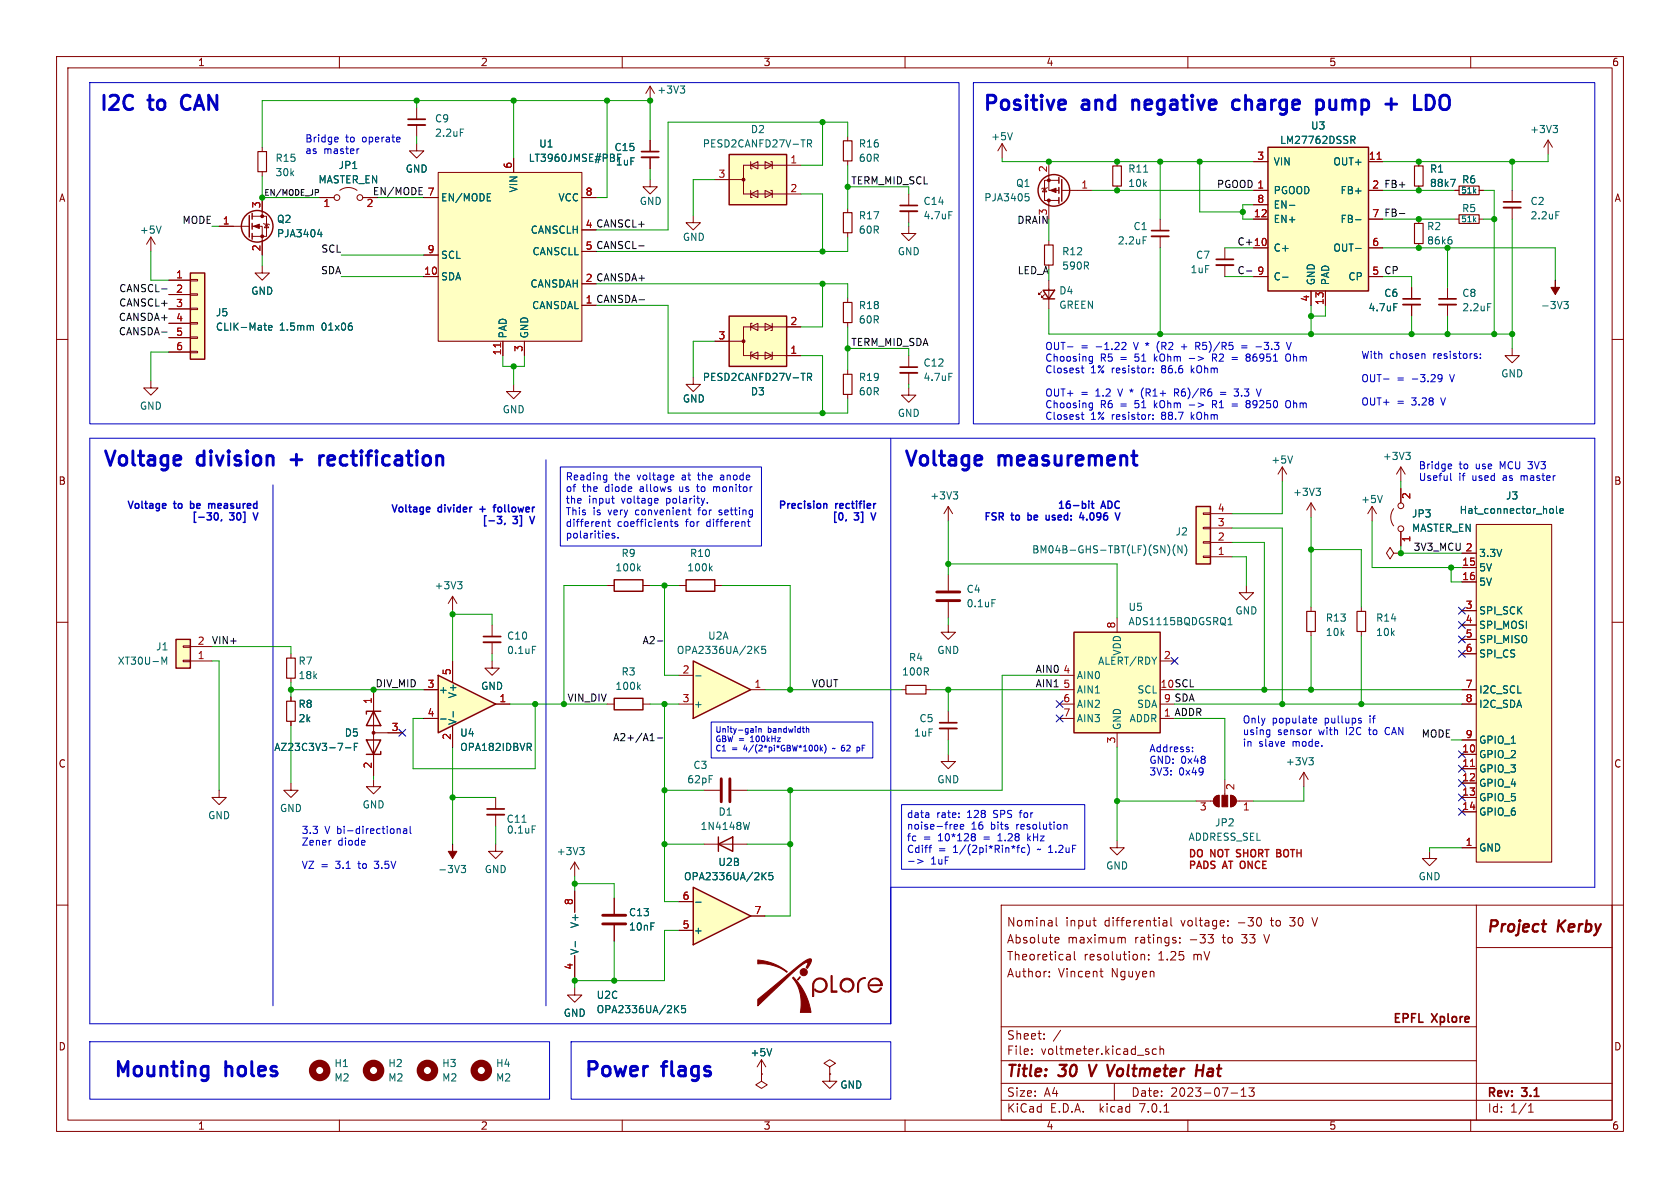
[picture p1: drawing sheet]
<svg xmlns="http://www.w3.org/2000/svg" width="297mm" height="210mm" viewBox="0 0 297 210" stroke-linecap="round" stroke-linejoin="round" font-family="sans-serif">
<defs><g id="words">
<g font-size="3.5" fill="#0000c2">
<text x="17.8" y="19.7">I2C</text>
<text x="26.6" y="19.7">to</text>
<text x="33.1" y="19.7">CAN</text>
<text x="174" y="19.7">Positive</text>
<text x="191.6" y="19.7">and</text>
<text x="201.2" y="19.7">negative</text>
<text x="219.7" y="19.7">charge</text>
<text x="235.2" y="19.7">pump</text>
<text x="248.2" y="19.7">+</text>
<text x="254" y="19.7">LDO</text>
<text x="18.4" y="82.6">Voltage</text>
<text x="35.1" y="82.6">division</text>
<text x="52.4" y="82.6">+</text>
<text x="58.2" y="82.6">rectification</text>
<text x="160" y="82.6">Voltage</text>
<text x="176.7" y="82.6">measurement</text>
<text x="20.3" y="190.5">Mounting</text>
<text x="40.1" y="190.5">holes</text>
<text x="103.5" y="190.5">Power</text>
<text x="117.5" y="190.5">flags</text>
</g>
<g font-size="2.8" fill="#840000">
<text x="262.7" y="165.3">Project</text>
<text x="275.2" y="165.3">Kerby</text>
<text x="178" y="190.8">Title:</text>
<text x="187.4" y="190.8">30</text>
<text x="193.3" y="190.8">V Voltmeter</text>
<text x="213.3" y="190.8">Hat</text>
</g>
<g font-size="2.1" fill="#840000">
<text x="178" y="166.9">Absolute</text>
<text x="178" y="163.9">Nominal</text>
<text x="188.4" y="163.9">input</text>
<text x="188.7" y="166.9">maximum</text>
<text x="195.2" y="163.9">differential</text>
<text x="200.6" y="166.9">ratings:</text>
<text x="208.8" y="163.9">voltage:</text>
<text x="210.3" y="166.9">-33</text>
<text x="216.3" y="166.9">to</text>
<text x="218.9" y="163.9">-30</text>
<text x="219.7" y="166.9">33</text>
<text x="223.8" y="166.9">V</text>
<text x="224.8" y="163.9">to</text>
<text x="228.3" y="163.9">30</text>
<text x="232.4" y="163.9">V</text>
<text x="178" y="172.9">Author:</text>
<text x="178" y="169.9">Theoretical</text>
<text x="187.1" y="172.9">Vincent</text>
<text x="191.6" y="169.9">resolution:</text>
<text x="196.4" y="172.9">Nguyen</text>
<text x="204.7" y="169.9">1.25</text>
<text x="211" y="169.9">mV</text>
<text x="178" y="183.9">Sheet:</text>
<text x="186.2" y="183.9">/</text>
<text x="245.9" y="181.1">EPFL</text>
<text x="252.9" y="181.1">Xplore</text>
<text x="178" y="186.6">File:</text>
<text x="184" y="186.6">voltmeter.kicad_sch</text>
<text x="178" y="196.8">KiCad</text>
<text x="178" y="194">Size:</text>
<text x="184.6" y="194">A4</text>
<text x="185.7" y="196.8">E.D.A.</text>
<text x="194.4" y="196.8">kicad</text>
<text x="200" y="194">Date:</text>
<text x="201.5" y="196.8">7.0.1</text>
<text x="206.9" y="194">2023-07-13</text>
<text x="263" y="194.2">Rev:</text>
<text x="263" y="196.8">Id:</text>
<text x="267" y="196.8">1/1</text>
<text x="269.2" y="194.2">3.1</text>
</g>
<g font-size="1.8" fill="#840000">
<text x="35" y="11.8">1</text>
<text x="85" y="11.8">2</text>
<text x="135" y="11.8">3</text>
<text x="185" y="11.8">4</text>
<text x="235" y="11.8">5</text>
<text x="285" y="11.8">6</text>
<text x="10.4" y="35.8">A</text>
<text x="285.4" y="35.8">A</text>
<text x="10.3" y="85.8">B</text>
<text x="285.3" y="85.8">B</text>
<text x="10.3" y="135.8">C</text>
<text x="285.3" y="135.8">C</text>
<text x="10.3" y="185.8">D</text>
<text x="285.3" y="185.8">D</text>
<text x="35" y="199.8">1</text>
<text x="85" y="199.8">2</text>
<text x="135" y="199.8">3</text>
<text x="185" y="199.8">4</text>
<text x="235" y="199.8">5</text>
<text x="285" y="199.8">6</text>
</g>
<g font-size="1.8" fill="#006464">
<text x="116.1" y="16.7">+3V3</text>
<text x="76.8" y="21.8">C9</text>
<text x="132.7" y="23.7">D2</text>
<text x="231.7" y="23.1">U3</text>
<text x="270.4" y="23.7">+3V3</text>
<text x="48.6" y="28.8">R15</text>
<text x="76.8" y="24.3">2.2uF</text>
<text x="93.4" y="28.8">LT3960JMSE#PBF</text>
<text x="95.3" y="26.2">U1</text>
<text x="108.6" y="26.9">C15</text>
<text x="108.8" y="29.4">1uF</text>
<text x="124.2" y="26.2">PESD2CANFD27V-TR</text>
<text x="151.8" y="26.2">R16</text>
<text x="151.8" y="28.8">60R</text>
<text x="175.2" y="25">+5V</text>
<text x="225.2" y="29.4">VIN</text>
<text x="226.2" y="25.6">LM27762DSSR</text>
<text x="235.6" y="29.4">OUT+</text>
<text x="48.6" y="31.3">30k</text>
<text x="56.2" y="32.6">MASTER_EN</text>
<text x="59.8" y="30">JP1</text>
<text x="71.7" y="30.7">GND</text>
<text x="78" y="35.8">EN/MODE</text>
<text x="91.6" y="34.1" transform="rotate(-90 91.6 34.1)">VIN</text>
<text x="98.6" y="35.8">VCC</text>
<text x="173.9" y="35.8">PJA3405</text>
<text x="179.6" y="33.2">Q1</text>
<text x="199.4" y="30.7">R11</text>
<text x="199.4" y="33.2">10k</text>
<text x="225.2" y="34.5">PGOOD</text>
<text x="236.9" y="34.5">FB+</text>
<text x="252.7" y="30.7">R1</text>
<text x="252.7" y="33.2">88k7</text>
<text x="258.4" y="32.6">R6</text>
<text x="24.7" y="41.5">+5V</text>
<text x="48.9" y="39.6">Q2</text>
<text x="93.7" y="41.5">CANSCLH</text>
<text x="113" y="36.4">GND</text>
<text x="151.8" y="38.9">R17</text>
<text x="151.8" y="41.5">60R</text>
<text x="163.2" y="36.4">C14</text>
<text x="163.2" y="38.9">4.7uF</text>
<text x="200.3" y="40.8">C1</text>
<text x="225.2" y="39.6">EN+</text>
<text x="225.2" y="37">EN-</text>
<text x="236.9" y="39.6">FB-</text>
<text x="252.2" y="40.8">R2</text>
<text x="258.4" y="37.7">R5</text>
<text x="270.5" y="36.4">C2</text>
<text x="270.5" y="38.9">2.2uF</text>
<text x="48.9" y="42.1">PJA3404</text>
<text x="78" y="45.9">SCL</text>
<text x="94" y="45.3">CANSCLL</text>
<text x="120.7" y="42.7">GND</text>
<text x="158.7" y="45.3">GND</text>
<text x="187.7" y="45.3">R12</text>
<text x="187.7" y="47.8">590R</text>
<text x="197.5" y="43.4">2.2uF</text>
<text x="211.4" y="45.9">C7</text>
<text x="225.2" y="44.6">C+</text>
<text x="235.6" y="44.6">OUT-</text>
<text x="252.2" y="43.4">86k6</text>
<text x="44.4" y="52.3">GND</text>
<text x="78" y="49.7">SDA</text>
<text x="93.6" y="51">CANSDAH</text>
<text x="187.2" y="52.2">D4</text>
<text x="210.4" y="48.5">1uF</text>
<text x="225.2" y="49.7">C-</text>
<text x="232.6" y="50.4" transform="rotate(-90 232.6 50.4)">GND</text>
<text x="235.1" y="50.4" transform="rotate(-90 235.1 50.4)">PAD</text>
<text x="238.3" y="49.7">CP</text>
<text x="244.7" y="52.6">C6</text>
<text x="258.5" y="52.6">C8</text>
<text x="38.1" y="56.1">J5</text>
<text x="38.1" y="58.6">CLIK-Mate</text>
<text x="49.4" y="58.6">1.5mm</text>
<text x="56.9" y="58.6">01x06</text>
<text x="89.7" y="59.8" transform="rotate(-90 89.7 59.8)">PAD</text>
<text x="93.5" y="59.8" transform="rotate(-90 93.5 59.8)">GND</text>
<text x="93.9" y="54.8">CANSDAL</text>
<text x="151.8" y="54.8">R18</text>
<text x="151.8" y="57.3">60R</text>
<text x="187.2" y="54.7">GREEN</text>
<text x="241.9" y="55.2">4.7uF</text>
<text x="258.5" y="55.2">2.2uF</text>
<text x="272.4" y="54.8">-3V3</text>
<text x="163.2" y="65">C12</text>
<text x="120.7" y="71.3">GND</text>
<text x="124.2" y="67.5">PESD2CANFD27V-TR</text>
<text x="132.7" y="70">D3</text>
<text x="151.8" y="67.5">R19</text>
<text x="151.8" y="70">60R</text>
<text x="163.2" y="67.5">4.7uF</text>
<text x="265.3" y="66.9">GND</text>
<text x="24.7" y="72.6">GND</text>
<text x="88.8" y="73.2">GND</text>
<text x="158.7" y="73.9">GND</text>
<text x="224.7" y="82.1">+5V</text>
<text x="244.4" y="81.5">+3V3</text>
<text x="164.4" y="88.5">+3V3</text>
<text x="228.5" y="87.8">+3V3</text>
<text x="240.6" y="89.1">+5V</text>
<text x="266.2" y="88.5">J3</text>
<text x="207.8" y="94.8">J2</text>
<text x="249.6" y="91.6">JP3</text>
<text x="249.6" y="94.2">MASTER_EN</text>
<text x="258" y="91">Hat_connector_hole</text>
<text x="108.7" y="101.2">100k</text>
<text x="109.8" y="98.6">R9</text>
<text x="121.4" y="101.2">100k</text>
<text x="121.9" y="98.6">R10</text>
<text x="182.4" y="98">BM04B-GHS-TBT(LF)(SN)(N)</text>
<text x="261.5" y="101.2">5V</text>
<text x="261.5" y="98.6">3.3V</text>
<text x="76.8" y="104.3">+3V3</text>
<text x="170.8" y="105">C4</text>
<text x="170.8" y="107.5">0.1uF</text>
<text x="261.5" y="103.7">5V</text>
<text x="89.6" y="113.2">C10</text>
<text x="125.1" y="113.2">U2A</text>
<text x="199.4" y="110.7">ADS1115BQDGSRQ1</text>
<text x="199.4" y="108.1">U5</text>
<text x="218.3" y="108.8">GND</text>
<text x="234.3" y="110">R13</text>
<text x="234.3" y="112.6">10k</text>
<text x="243.2" y="110">R14</text>
<text x="243.2" y="112.6">10k</text>
<text x="261.5" y="108.8">SPI_SCK</text>
<text x="261.5" y="111.3">SPI_MOSI</text>
<text x="261.5" y="113.9">SPI_MISO</text>
<text x="20.8" y="117.7">XT30U-M</text>
<text x="27.5" y="115.1">J1</text>
<text x="52.7" y="117.7">R7</text>
<text x="89.6" y="115.8">0.1uF</text>
<text x="109.8" y="119.6">R3</text>
<text x="119.6" y="115.8">OPA2336UA/2K5</text>
<text x="159.4" y="119.6">100R</text>
<text x="160.6" y="117">R4</text>
<text x="165.6" y="115.8">GND</text>
<text x="194" y="117.7">ALERT/RDY</text>
<text x="198.3" y="116" transform="rotate(-90 198.3 116)">VDD</text>
<text x="261.5" y="116.4">SPI_CS</text>
<text x="52.7" y="125.3">R8</text>
<text x="52.7" y="120.2">18k</text>
<text x="77.6" y="122.7">+</text>
<text x="80.8" y="123.6" transform="rotate(-90 80.8 123.6)">V+</text>
<text x="85" y="122.1">GND</text>
<text x="108.7" y="122.1">100k</text>
<text x="122.7" y="125.3">+</text>
<text x="190.4" y="120.2">AIN0</text>
<text x="190.4" y="122.7">AIN1</text>
<text x="190.4" y="125.3">AIN2</text>
<text x="200.9" y="125.3">SDA</text>
<text x="201" y="122.7">SCL</text>
<text x="261.5" y="122.7">I2C_SCL</text>
<text x="261.5" y="125.3">I2C_SDA</text>
<text x="52.7" y="127.8">2k</text>
<text x="60.9" y="130.4">D5</text>
<text x="80.8" y="128.1" transform="rotate(-90 80.8 128.1)">V-</text>
<text x="81.3" y="130.4">U4</text>
<text x="161.5" y="130.4">1uF</text>
<text x="162.5" y="127.8">C5</text>
<text x="190.4" y="127.8">AIN3</text>
<text x="198.3" y="129" transform="rotate(-90 198.3 129)">GND</text>
<text x="199.6" y="127.8">ADDR</text>
<text x="261.5" y="131.6">GPIO_1</text>
<text x="48.4" y="132.9">AZ23C3V3-7-F</text>
<text x="81.3" y="132.9">OPA182IDBVR</text>
<text x="122.5" y="136.1">C3</text>
<text x="227.3" y="135.4">+3V3</text>
<text x="261.5" y="134.2">GPIO_2</text>
<text x="261.5" y="136.7">GPIO_3</text>
<text x="49.4" y="143.7">GND</text>
<text x="64" y="143.1">GND</text>
<text x="121.4" y="138.6">62pF</text>
<text x="165.6" y="138.6">GND</text>
<text x="261.5" y="139.3">GPIO_4</text>
<text x="261.5" y="141.8">GPIO_5</text>
<text x="36.7" y="145">GND</text>
<text x="89.5" y="145.6">C11</text>
<text x="89.5" y="147.5">0.1uF</text>
<text x="123.8" y="146.9">1N4148W</text>
<text x="127" y="144.3">D1</text>
<text x="210.1" y="148.8">ADDRESS_SEL</text>
<text x="214.7" y="146.2">JP2</text>
<text x="261.5" y="144.3">GPIO_6</text>
<text x="77.4" y="154.5">-3V3</text>
<text x="85.6" y="154.5">GND</text>
<text x="98.4" y="151.3">+3V3</text>
<text x="120.9" y="155.8">OPA2336UA/2K5</text>
<text x="126.9" y="153.2">U2B</text>
<text x="195.5" y="153.9">GND</text>
<text x="250.7" y="155.8">GND</text>
<text x="261.5" y="150.7">GND</text>
<text x="102.4" y="164.2" transform="rotate(-90 102.4 164.2)">V+</text>
<text x="111.1" y="162.1">C13</text>
<text x="111.1" y="164.7">10nF</text>
<text x="122.7" y="165.3">+</text>
<text x="102.4" y="168.8" transform="rotate(-90 102.4 168.8)">V-</text>
<text x="99.6" y="179.9">GND</text>
<text x="105.4" y="176.7">U2C</text>
<text x="105.4" y="179.3">OPA2336UA/2K5</text>
<text x="59.1" y="188.8">H1</text>
<text x="59.1" y="191.3">M2</text>
<text x="68.6" y="188.8">H2</text>
<text x="68.6" y="191.3">M2</text>
<text x="78.1" y="188.8">H3</text>
<text x="78.1" y="191.3">M2</text>
<text x="87.6" y="188.8">H4</text>
<text x="87.6" y="191.3">M2</text>
<text x="132.6" y="186.9">+5V</text>
<text x="148.5" y="192.6">GND</text>
</g>
<g font-size="1.8" fill="#0000c2">
<text x="54" y="25.2">Bridge</text>
<text x="54" y="27.3">as</text>
<text x="57.2" y="27.3">master</text>
<text x="61.1" y="25.2">to</text>
<text x="64.1" y="25.2">operate</text>
<text x="184.8" y="62">OUT-</text>
<text x="184.8" y="64">Choosing</text>
<text x="191.1" y="62">=</text>
<text x="193.7" y="62">-1.22</text>
<text x="194.5" y="64">R5</text>
<text x="198.1" y="64">=</text>
<text x="200.6" y="62">V *</text>
<text x="200.8" y="64">51</text>
<text x="204.3" y="64">kOhm</text>
<text x="204.9" y="62">(R2</text>
<text x="209.3" y="62">+</text>
<text x="212" y="62">R5)/R5</text>
<text x="214.8" y="64">R2</text>
<text x="221.1" y="64">86951</text>
<text x="222.9" y="62">-3.3</text>
<text x="228.2" y="64">Ohm</text>
<text x="240.7" y="63.5">With</text>
<text x="245.7" y="63.5">chosen</text>
<text x="253.4" y="63.5">resistors:</text>
<text x="184.8" y="66.1">Closest</text>
<text x="184.8" y="70.2">OUT+</text>
<text x="191.1" y="70.2">=</text>
<text x="192.8" y="66.1">1% resistor:</text>
<text x="193.7" y="70.2">1.2</text>
<text x="197.9" y="70.2">V *</text>
<text x="202.1" y="70.2">(R1+</text>
<text x="205.5" y="66.1">86.6</text>
<text x="208.1" y="70.2">R6)/R6</text>
<text x="210.8" y="66.1">kOhm</text>
<text x="219" y="70.2">3.3</text>
<text x="240.7" y="67.6">OUT-</text>
<text x="240.7" y="71.8">OUT+</text>
<text x="247" y="67.6">=</text>
<text x="247" y="71.8">=</text>
<text x="249.6" y="67.6">-3.29</text>
<text x="249.6" y="71.8">3.28</text>
<text x="255" y="71.8">V</text>
<text x="256.5" y="67.6">V</text>
<text x="184.8" y="72.2">Choosing</text>
<text x="184.8" y="74.3">Closest</text>
<text x="192.8" y="74.3">1% resistor:</text>
<text x="194.5" y="72.2">R6</text>
<text x="198.1" y="72.2">=</text>
<text x="200.8" y="72.2">51</text>
<text x="204.3" y="72.2">kOhm</text>
<text x="205.5" y="74.3">88.7</text>
<text x="210.8" y="74.3">kOhm</text>
<text x="214.8" y="72.2">R1</text>
<text x="221.1" y="72.2">89250</text>
<text x="228.2" y="72.2">Ohm</text>
<text x="250.8" y="83">Bridge</text>
<text x="258" y="83">to</text>
<text x="260.9" y="83">use</text>
<text x="265.3" y="83">MCU 3V3</text>
<text x="100" y="85.2">Reading</text>
<text x="100" y="87.2">of</text>
<text x="100" y="89.3">the</text>
<text x="103" y="87.2">the</text>
<text x="104.1" y="89.3">input</text>
<text x="107" y="87.2">diode</text>
<text x="108.7" y="85.2">the</text>
<text x="109.9" y="89.3">voltage</text>
<text x="112.7" y="85.2">voltage</text>
<text x="113.3" y="87.2">allows</text>
<text x="117.9" y="89.3">polarity.</text>
<text x="120.4" y="87.2">us</text>
<text x="120.7" y="85.2">at</text>
<text x="123.6" y="87.2">to</text>
<text x="123.7" y="85.2">the</text>
<text x="126.6" y="87.2">monitor</text>
<text x="127.7" y="85.2">anode</text>
<text x="250.8" y="85.1">Useful</text>
<text x="257.9" y="85.1">if</text>
<text x="260.3" y="85.1">used</text>
<text x="265.8" y="85.1">as</text>
<text x="269.1" y="85.1">master</text>
<text x="22.2" y="90">Voltage</text>
<text x="30.5" y="90">to</text>
<text x="33.6" y="92.1">[-30,</text>
<text x="33.8" y="90">be</text>
<text x="37.4" y="90">measured</text>
<text x="40.4" y="92.1">30]</text>
<text x="45" y="92.1">V</text>
<text x="68.8" y="90.7">Voltage</text>
<text x="77.2" y="90.7">divider</text>
<text x="84.9" y="90.7">+</text>
<text x="84.9" y="92.7">[-3,</text>
<text x="87.8" y="90.7">follower</text>
<text x="90.5" y="92.7">3]</text>
<text x="93.9" y="92.7">V</text>
<text x="100" y="91.3">This</text>
<text x="100" y="93.4">different</text>
<text x="100" y="95.4">polarities.</text>
<text x="104.9" y="91.3">is</text>
<text x="107.6" y="91.3">very</text>
<text x="109.2" y="93.4">coefficients</text>
<text x="112.5" y="91.3">convenient</text>
<text x="121.3" y="93.4">for</text>
<text x="123.7" y="91.3">for</text>
<text x="125.1" y="93.4">different</text>
<text x="127.5" y="91.3">setting</text>
<text x="137.3" y="90">Precision</text>
<text x="146.8" y="92.1">[0,</text>
<text x="147.4" y="90">rectifier</text>
<text x="150.8" y="92.1">3]</text>
<text x="154.2" y="92.1">V</text>
<text x="173.7" y="92.1">FSR</text>
<text x="178.6" y="92.1">to</text>
<text x="181.8" y="92.1">be</text>
<text x="185.4" y="92.1">used:</text>
<text x="186.7" y="90">16-bit</text>
<text x="191.8" y="92.1">4.096</text>
<text x="194.5" y="90">ADC</text>
<text x="219.7" y="128">Only</text>
<text x="219.7" y="130">using</text>
<text x="224.9" y="128">populate</text>
<text x="225.9" y="130">sensor</text>
<text x="233.2" y="130">with</text>
<text x="234.2" y="128">pullups</text>
<text x="238.1" y="130">I2C</text>
<text x="242.3" y="128">if</text>
<text x="242.3" y="130">to</text>
<text x="245.3" y="130">CAN</text>
<text x="203.2" y="133">Address:</text>
<text x="203.2" y="135.1">GND: 0x48</text>
<text x="203.2" y="137.2">3V3:</text>
<text x="208.4" y="137.2">0x49</text>
<text x="219.7" y="132.1">in</text>
<text x="222.6" y="132.1">slave</text>
<text x="228.6" y="132.1">mode.</text>
<text x="53.3" y="147.5">3.3</text>
<text x="53.3" y="149.6">Zener</text>
<text x="57.5" y="147.5">V bi-directional</text>
<text x="59.8" y="149.6">diode</text>
<text x="160.3" y="144.8">data</text>
<text x="160.3" y="146.9">noise-free</text>
<text x="160.3" y="149">fc</text>
<text x="163.2" y="149">=</text>
<text x="165.6" y="144.8">rate:</text>
<text x="165.9" y="149">10*128</text>
<text x="171.1" y="144.8">128</text>
<text x="171.7" y="146.9">16</text>
<text x="174" y="149">=</text>
<text x="175.2" y="146.9">bits</text>
<text x="175.8" y="144.8">SPS</text>
<text x="176.7" y="149">1.28</text>
<text x="179.8" y="146.9">resolution</text>
<text x="180.6" y="144.8">for</text>
<text x="182" y="149">kHz</text>
<text x="53.3" y="153.7">VZ =</text>
<text x="59.4" y="153.7">3.1</text>
<text x="63.5" y="153.7">to</text>
<text x="66.5" y="153.7">3.5V</text>
<text x="160.3" y="151">Cdiff</text>
<text x="164.6" y="153.1">1uF</text>
<text x="165.9" y="151">=</text>
<text x="168.6" y="151">1/(2pi*Rin*fc)</text>
<text x="183.6" y="151">~ 1.2uF</text>
</g>
<g font-size="1.8" fill="#a90000">
<text x="90.6" y="29.9" transform="rotate(-90 90.6 29.9)">6</text>
<text x="139.7" y="29">1</text>
<text x="222.2" y="28.3">3</text>
<text x="241.9" y="28.3">11</text>
<text x="75.5" y="34.7">7</text>
<text x="103.5" y="34.7">8</text>
<text x="127" y="31.5">3</text>
<text x="139.7" y="34">2</text>
<text x="185.2" y="30.5" transform="rotate(-90 185.2 30.5)">2</text>
<text x="191.1" y="33.4">1</text>
<text x="222.2" y="35.9">8</text>
<text x="222.2" y="33.4">1</text>
<text x="242.5" y="33.4">2</text>
<text x="39.3" y="39.8">1</text>
<text x="46.1" y="36.9" transform="rotate(-90 46.1 36.9)">3</text>
<text x="57.1" y="36.8">1</text>
<text x="64.7" y="36.8">2</text>
<text x="103.5" y="40.4">4</text>
<text x="185.2" y="38.1" transform="rotate(-90 185.2 38.1)">3</text>
<text x="221.6" y="38.5">12</text>
<text x="242.5" y="38.5">7</text>
<text x="46.1" y="44.5" transform="rotate(-90 46.1 44.5)">2</text>
<text x="75.5" y="44.8">9</text>
<text x="103.5" y="44.2">5</text>
<text x="221.6" y="43.6">10</text>
<text x="242.5" y="43.6">6</text>
<text x="31.1" y="49.3">1</text>
<text x="31.1" y="51.8">2</text>
<text x="74.9" y="48.6">10</text>
<text x="103.5" y="53.7">1</text>
<text x="103.5" y="49.9">2</text>
<text x="222.2" y="48.6">9</text>
<text x="231.5" y="53.4" transform="rotate(-90 231.5 53.4)">4</text>
<text x="234.1" y="54" transform="rotate(-90 234.1 54)">13</text>
<text x="242.5" y="48.6">5</text>
<text x="31.1" y="54.4">3</text>
<text x="31.1" y="56.9">4</text>
<text x="31.1" y="59.4">5</text>
<text x="139.7" y="57.5">2</text>
<text x="31.1" y="62">6</text>
<text x="88.6" y="62.9" transform="rotate(-90 88.6 62.9)">11</text>
<text x="92.5" y="62.3" transform="rotate(-90 92.5 62.3)">3</text>
<text x="127" y="60.1">3</text>
<text x="139.7" y="62.6">1</text>
<text x="249.6" y="88.3" transform="rotate(-90 249.6 88.3)">2</text>
<text x="215.2" y="95.6">2</text>
<text x="215.2" y="93.1">3</text>
<text x="215.2" y="90.6">4</text>
<text x="249.6" y="95.9" transform="rotate(-90 249.6 95.9)">1</text>
<text x="215.2" y="98.2">1</text>
<text x="258.4" y="100.1">15</text>
<text x="259" y="97.5">2</text>
<text x="258.4" y="102.6">16</text>
<text x="259" y="107.7">3</text>
<text x="197.2" y="111.2" transform="rotate(-90 197.2 111.2)">8</text>
<text x="259" y="110.2">4</text>
<text x="259" y="112.8">5</text>
<text x="34.9" y="116.6">1</text>
<text x="34.9" y="114">2</text>
<text x="79.8" y="119.4" transform="rotate(-90 79.8 119.4)">5</text>
<text x="120.6" y="119.1">2</text>
<text x="187.9" y="119.1">4</text>
<text x="205.7" y="116.6">2</text>
<text x="259" y="115.3">6</text>
<text x="65.8" y="124.5" transform="rotate(-90 65.8 124.5)">1</text>
<text x="75.5" y="121.7">3</text>
<text x="88.2" y="124.2">1</text>
<text x="120.6" y="124.2">3</text>
<text x="133.3" y="121.7">1</text>
<text x="187.9" y="121.7">5</text>
<text x="187.9" y="124.2">6</text>
<text x="259" y="121.7">7</text>
<text x="259" y="124.2">8</text>
<text x="69.2" y="129.3">3</text>
<text x="75.5" y="126.7">4</text>
<text x="79.8" y="130.8" transform="rotate(-90 79.8 130.8)">2</text>
<text x="187.9" y="126.7">7</text>
<text x="197.2" y="131.5" transform="rotate(-90 197.2 131.5)">3</text>
<text x="259" y="130.6">9</text>
<text x="65.8" y="135.9" transform="rotate(-90 65.8 135.9)">2</text>
<text x="258.4" y="133.1">10</text>
<text x="258.4" y="135.6">11</text>
<text x="212.1" y="143.5">3</text>
<text x="218.4" y="139.7" transform="rotate(-90 218.4 139.7)">2</text>
<text x="219.7" y="143.5">1</text>
<text x="258.4" y="138.2">12</text>
<text x="258.4" y="140.7">13</text>
<text x="258.4" y="143.3">14</text>
<text x="259" y="149.6">1</text>
<text x="101.3" y="160.1" transform="rotate(-90 101.3 160.1)">8</text>
<text x="120.6" y="159.1">6</text>
<text x="133.3" y="161.7">7</text>
<text x="120.6" y="164.2">5</text>
<text x="101.3" y="171.5" transform="rotate(-90 101.3 171.5)">4</text>
</g>
<g font-size="1.8" fill="#0f0f0f">
<text x="65.8" y="34.6">EN/MODE</text>
<text x="150.5" y="32.7">TERM_MID_SCL</text>
<text x="215" y="33.3">PGOOD 1</text>
<text x="242.5" y="33.4">2 FB+</text>
<text x="32.1" y="39.7">MODE</text>
<text x="103.5" y="40.4">4 CANSCL+</text>
<text x="179.7" y="39.7">DRAIN</text>
<text x="242.5" y="38.5">7 FB-</text>
<text x="56.7" y="44.7">SCL</text>
<text x="103.5" y="44.2">5 CANSCL-</text>
<text x="218.6" y="43.5">C+ 10</text>
<text x="20.9" y="51.7">CANSCL-</text>
<text x="56.6" y="48.5">SDA</text>
<text x="103.5" y="53.7">1 CANSDA-</text>
<text x="103.5" y="49.9">2 CANSDA+</text>
<text x="179.8" y="48.5">LED_A</text>
<text x="218.6" y="48.5">C-</text>
<text x="242.5" y="48.6">5 CP</text>
<text x="20.9" y="56.8">CANSDA+</text>
<text x="20.9" y="59.3">CANSDA-</text>
<text x="20.9" y="54.3">CANSCL+</text>
<text x="150.5" y="61.2">TERM_MID_SDA</text>
<text x="249.8" y="97.4">3V3_MCU 2</text>
<text x="37.5" y="114">VIN+</text>
<text x="113.5" y="114">A2-</text>
<text x="183" y="119">AIN0</text>
<text x="66.3" y="121.6">DIV_MID</text>
<text x="100.3" y="124.1">VIN_DIV</text>
<text x="143.5" y="121.6">VOUT</text>
<text x="183" y="121.6">AIN1</text>
<text x="205.1" y="121.7">10 SCL</text>
<text x="205.7" y="124.2">9 SDA</text>
<text x="108.3" y="131.1">A2+/A1-</text>
<text x="205.7" y="126.7">1 ADDR</text>
<text x="251.2" y="130.5">MODE</text>
</g>
<g font-size="1.8" fill="#f00">
<text x="210.2" y="151.6">DO</text>
<text x="210.2" y="153.7">PADS</text>
<text x="214.1" y="151.6">NOT</text>
<text x="216.4" y="153.7">AT ONCE</text>
<text x="219.1" y="151.6">SHORT</text>
<text x="226.6" y="151.6">BOTH</text>
</g>
<text font-size="1.4" fill="#0f0f0f" x="46.6" y="34.6">EN/MODE_JP</text>
<g font-size="1.4" fill="#006464">
<text x="258.2" y="34.4">51k</text>
<text x="258.2" y="39.4">51k</text>
</g>
<g font-size="1.4" fill="#0000c2">
<text x="126.5" y="129.8">Unity-gain</text>
<text x="126.5" y="131.4">GBW =</text>
<text x="132.8" y="131.4">100kHz</text>
<text x="135.8" y="129.8">bandwidth</text>
<text x="126.5" y="133.1">C1</text>
<text x="129.4" y="133.1">=</text>
<text x="131.6" y="133.1">4/(2*pi*GBW*100k)</text>
<text x="147.6" y="133.1">~ 62</text>
<text x="152.2" y="133.1">pF</text>
</g>
</g></defs>
<g fill="none" stroke="#840000" stroke-width=".18">
<path d="M10 10h277v190h-277zM12 12h273v186h-273zM60 10v2M73.7 19.1v2M110 10v2M160 10v2M210 10v2M260 10v2M73.7 25.4v1.3h1.2l-1.2 1.2-1.3-1.2h1.3M73.7 22.1v2M126.4 31.8h5M132.7 33.7v1.2h.3"/>
<path d="M132.7 28.6v1.2h.3M132.7 34.3l1.3-.6v1.2zM132.7 29.2l1.3-.6v1.2zM135.3 33.7l1.2 .6-1.2 .6zM135.3 28.6l1.2 .6-1.2 .6zM136.3 33.7h.2v1.2M136.3 28.6h.2v1.2M141.6 29.2h-10.2v5.1h10.2M10 60h2M132.7 57.8l1.3-.6v1.2zM133 57.2h-.3v1.2M135.3 57.2l1.2 .6-1.2 .6z"/>
<path d="M136.5 57.2v1.2h-.2M141.6 57.8h-10.2v5.1h10.2M285 60h2M126.4 60.3h5M132.7 62.9l1.3-.7v1.3zM133 62.2h-.3v1.3M135.3 62.2l1.2 .7-1.2 .6zM136.5 62.2v1.3h-.2M10 110h2M167.6 101.6v2.8M167.6 106.4v2.8M285 110h2"/>
<path d="M107.3 124.5h1.3M113.7 124.5h1.2M10 160h2M87.6 149.2v1.3h1.3l-1.3 1.3-1.2-1.3h1.2M87.6 141v2M87.6 144v2.1M101.6 152.4l-.8 1.3M101.6 152.4v2.5M101.6 157.5v3.8M101.6 152.4l.8 1.3M108.6 158.8v2.7M285 160h2"/>
<path d="M101.6 168.9v3.8M108.6 163.6v2.8M177 160h108v38h-108zM185.5 172.6v.1M185.5 171.8v.1M186.7 165.7l.4 .1 .1 .3-.7 .1M186.7 162.2v1.3l.2 .2M187.1 166.6l-.4 .1M188.7 168.7h.3l.2 .2v.8M189.2 169.6l-.5 .1M189.2 169.1h-.5M189.9 168.2v1.3l.2 .2"/>
<path d="M193.2 162.7h.6M193.5 163.6l.3 .1M194.4 171.7h.6M194.7 172.6l.3 .1M198.4 165.8h.5v.9M201.7 168.8l.2-.1 .4 .1 .1 .9M203.1 169.6v.1M203.1 168.8v.1M205.6 162.8h.6l.1 .9M206.3 163.1h-.5a.29 .29 0 0 0-.2 .3 .29 .29 0 0 0 .2 .3l.5-.1M207 162.2v1.3l.2 .2M208.6 166.6v.1"/>
<path d="M208.6 165.8v.1M213.6 165.2h.9l-.5 .6 .4 .1 .1 .5-.3 .3h-.4M217.1 163.6v.1M217.1 162.8v.1M222.5 162.2a.81 .81 0 0 1 .6 .6 .81 .81 0 0 1-.3 .8l-.3 .1M261 160v38M261 167.5h24M60 198v2M110 198v2M160 198v2M177 194.5h108M177 191.5h108"/>
<path d="M177 187.5h84M177 181.5h84M182.4 186.3v.1M182.4 185.5v.1M184.6 183.6v.1M184.6 182.8v.1M197 191.5v3M202.9 185.9l.2 .2-.2 .3M202.9 185.4l.2 .1M204.4 185.5l-.4-.1-.3 .3v.4l.2 .2h.5M205.1 185.5l.2-.1 .3 .1 .1 .9M205.1 184.9v1.5"/>
<path d="M205.8 196.6h.8M210 198v2M217.6 193.2h1.2M219.4 193.8h.9M219.4 192.7l.5-.4v1.5M220.8 192.3h.9l-.5 .6 .4 .1v.7l-.2 .1h-.4l-.2-.1M260 198v2M270.2 196.6h.9M270.2 195.5l.4-.4v1.5"/>
</g>
<path d="M272.6 163.3h.7M192.5 188.2l.4 2M211.5 189.2h1.2M211.6 188.2l-.2 2M212.8 188.2l-.3 2" fill="none" stroke="#840000" stroke-width=".4"/>
<path d="M165.6 106.2h4.1M165.6 104.6h4.1M106.6 163.3h4M106.6 161.8h4" fill="none" stroke="#840000" stroke-width=".51"/>
<g fill="none" stroke="#006464" stroke-width=".18">
<path d="M81.4 22.8h.6M142.8 25.4l.6-.1 .1-.2-.1-.3-.6-.1v1.3M143.1 25.4l.4 .6M142.8 66.7l.6-.1 .1-.2-.1-.3-.6-.1v1.3M143.1 66.7l.4 .6M175.4 106h.6M112.8 121.4l.4 .5M113.2 121l-.5 .5M81.5 153h.8l-.4 .5 .3 .1v.5l-.1 .2-.5-.1M94.1 146h.6M102.5 149.8h.8l-.5 .5M103 150.3l.3 .2v.3l-.3 .3"/>
<path d="M101.7 166.4v1M119.5 178.3l.5 .7M120 177.8l-.7 .7M121.1 177.8h-.6v.6l.2-.2 .4 .1 .1 .2-.1 .4-.1 .1-.5-.1"/>
</g>
<g fill="none" stroke="#840000" stroke-width="1.3">
<circle cx="75.6" cy="189.2" r="1.27"/>
<circle cx="85.1" cy="189.2" r="1.27"/>
</g>
<g fill="#ffffc2" stroke="#ffffc2" stroke-width=".18">
<path d="M128.9 27.3h10.2v8.9h-10.2z"/>
<path d="M128.9 55.9h10.2v8.9h-10.2z"/>
</g>
<path d="M128.9 27.3h10.2v8.9h-10.2zM128.9 55.9h10.2v8.9h-10.2zM108.6 123.4h5.1v2.1h-5.1z" fill="none" stroke="#840000" stroke-width=".25"/>
<g fill="#840000" stroke="#840000" stroke-width=".18">
<path d="M80 149.2v1.3h.8l-.8 1.3-.8-1.3h.8z"/>
<circle cx="131.4" cy="31.7" r=".25"/>
<circle cx="131.4" cy="60.3" r=".25"/>
</g>
<path d="M72.1 22.1h3.1M86.1 144h3.1" fill="none" stroke="#840000" stroke-width=".33"/>
<path d="M72.1 21.1h3.1M86.1 143h3.1" fill="none" stroke="#840000" stroke-width=".3"/>
<path d="M122.6 156.8l10.1 5.1-10.1 5.1z" fill="#ffffc2"/>
<path d="M31.1 113h2.6v5.1h-2.6zM121.3 102.5h5.1v2h-5.1zM189.9 111.8h15.2v17.7h-15.2zM64.8 130.8h2.5l-1.3 2.6zM66 125.7l1.3 2.6h-2.5zM67.3 125.7h-2.5v.5M67.3 132.8v.6h-2.5M122.6 156.8l10.1 5.1-10.1 5.1zM127 149.2l2.5-1.2v2.5zM127 148v2.5" fill="none" stroke="#840000" stroke-width=".25"/>
<g fill="none" stroke="#840000" stroke-width=".18">
<path d="M114.9 31.8v1.2h1.3l-1.3 1.3-1.2-1.3h1.2M114.9 24.8v2M114.9 27.8v2M122.6 38.1v1.3h1.2l-1.2 1.2-1.3-1.2h1.3M149.9 36.8v.8M177.2 25.4l-.8 1.3M177.2 25.4v2.5M177.2 25.4l.7 1.3M149.9 41.1v.8M160.7 40v1.3h1.2l-1.2 1.2-1.3-1.2h1.3M26.7 67.3v1.3h1.2l-1.2 1.3-1.3-1.3h1.3M122.6 66.7v1.2h1.2l-1.2 1.3-1.3-1.3h1.3"/>
<path d="M149.9 65.4v.8M149.9 69.7v.8M267.3 61.6v1.3h1.3l-1.3 1.2-1.2-1.2h1.2M167.6 89.5l-.7 1.3M167.6 89.5v2.6M167.6 89.5l.8 1.3M231.8 88.9l-.8 1.3M231.8 88.9v2.5M231.8 88.9l.7 1.3M242.6 89.5l-.8 1.3M242.6 89.5v2.6M242.6 89.5l.7 1.3"/>
<path d="M246.4 97.8l-.7-1-.6 1 .6 1 .7-1h1.2M247.6 97.8h.1M32.4 114.2h1.3v.2h-1.3zM32.4 116.7h1.3v.3h-1.3zM33.7 116.8h3.8M33.7 114.3h3.8M120 103.5h1.3M126.4 103.5h1.2M167.6 110.5v1.3h1.3l-1.3 1.2-1.2-1.2h1.2M187.3 119.4h2.6M197.5 109.2v2.6M205.1 116.8h2.5"/>
<path d="M220.3 103.5v1.3h1.3l-1.3 1.2-1.2-1.2h1.2M231.8 107.3v.8M231.8 111.6v.8M240.7 107.3v.8M240.7 111.6v.8M38.7 139.7v1.3h1.3l-1.3 1.2-1.2-1.2h1.2M51.4 138.4v1.3h1.3l-1.3 1.3-1.2-1.3h1.2M51.4 123.2v.8M51.4 127.5v.8M66 137.8v1.3h1.3l-1.3 1.2-1.2-1.2h1.2M66 121.9v3.8M66 126v11.2"/>
<path d="M66 129.5h5.1M124.5 139.7h2.8M129.3 139.7h2.8M159.4 121.9h.7M163.7 121.9h.8M167.6 125.7v2.1M167.6 128.8v2M187.3 121.9h2.6M187.3 127h2.6M187.3 124.5h2.6M197.5 129.5v2.6M205.1 127h2.5"/>
<path d="M205.1 124.5h2.5M120 159.4h2.6M124.5 149.2h7.6M101.6 174.6v1.3h1.3l-1.3 1.3-1.3-1.3h1.3M120 164.5h2.6M132.7 161.9h2.6M134.6 189.9v1.2l1 .7-1 .6-1-.6 1-.7M134.6 189.9h.1M134.6 187.3l-.7 1.3M134.6 187.3v2.6M134.6 187.3l.8 1.3M146.7 189.9v1.2h1.3l-1.3 1.3-1.3-1.3h1.3"/>
<path d="M146.7 188.6l1-.6-1-.7-1 .7 1 .6v1.3M146.7 189.9h.1"/>
</g>
<g fill="none" stroke="#006464" stroke-width=".18">
<path d="M179 23.4l-.4 1.3M168.5 86.9h.8l-.4 .5M169.1 87.4l.2 .3v.3l-.2 .2M232.7 86.3h.7l-.4 .5M233.2 86.8l.2 .2v.3l-.2 .3M244.4 87.6l-.4 1.3M28.6 116.2l.4 .9 .5-.9v1.2M125.5 100.4l.4 .5M125.9 100.1l-.5 .5M217.1 110.4h.7M217.2 109.5l.3-.3v1.2M61.1 132.2h.9"/>
<path d="M62.6 132h.5M63.2 131.4h-.6v1.3M123 159.5h1M132.5 145.4l-.3 1.2M134.9 154.8l.5 .7M135.4 154.3l-.7 .7M136.6 154.3h-.6l-.1 .6 .2-.2 .4 .1 .1 .2v.4l-.2 .1-.5-.1M136.4 185.4l-.4 1.2"/>
</g>
<path d="M113.4 27.8h3.1M166.1 128.8h3.1" fill="none" stroke="#840000" stroke-width=".33"/>
<path d="M113.4 26.8h3.1M166.1 127.8h3.1" fill="none" stroke="#840000" stroke-width=".3"/>
<path d="M127.5 137.7v4M129 137.7v4" fill="none" stroke="#840000" stroke-width=".51"/>
<g fill="#840000" stroke="#840000" stroke-width=".18">
<path d="M146.9 172.5h.2v2.7h.9v.2h-1.1z"/>
<path d="M141.4 172.7h.1l-.4 .6-.1-.1z"/>
<path d="M152 173.2l.6-.4h.4v.2a1.32 1.32 0 0 0-1.2 1.7v.7h-.2v-.9a1.67 1.67 0 0 1 .4-1.3z"/>
<path d="M140.3 172.7a11.4 11.4 0 0 1 3.1 6.3h-1.9v-.2a7.3 7.3 0 0 0-1.4-5.9z"/>
<path d="M134 169.7h.2a9.5 9.5 0 0 1 5 2.1l-.1 .1a7.2 7.2 0 0 0-5.1-1.5z"/>
<path d="M144.1 173.2a1.28 1.28 0 0 1 1.8 0 1.28 1.28 0 0 1 0 1.8 1.28 1.28 0 0 1-1.8 .1v-.3l.2 .2a1.07 1.07 0 0 0 1.6-.3 1.07 1.07 0 0 0-.7-1.6 1.07 1.07 0 0 0-1.3 .9l-.1 2.2h-.1v-1.7a1.46 1.46 0 0 1 .4-1.3z"/>
<path d="M148.9 173.3l.8-.4a1.24 1.24 0 0 1 1.3 1.2 1.24 1.24 0 0 1-1.1 1.3v-.2a1.02 1.02 0 0 0 .8-1.5 1.02 1.02 0 0 0-1.8-.1 1.02 1.02 0 0 0 .7 1.6v.2a1.24 1.24 0 0 1-1-.8 1.24 1.24 0 0 1 .3-1.3z"/>
<path d="M134 176.7l6.9-5.7 1.6-1.3a.56 .56 0 0 1 1 0l-.6 1.3a.17 .17 0 0 1-.2 .2 .17 .17 0 0 1-.1-.3l.2-.6a.18 .18 0 0 0-.1-.2 .18 .18 0 0 0-.2 0l-2 1.5-6.5 6.2z"/>
<path d="M153.8 173.3a1.26 1.26 0 0 1 1.4-.3 1.26 1.26 0 0 1 .8 1.2h-2.2v-.1h1.9a1.06 1.06 0 0 0-1.5-.9 1.06 1.06 0 0 0-.3 1.7 1.06 1.06 0 0 0 1.7-.2l.3-.1a1.26 1.26 0 0 1-1.9 .6 1.26 1.26 0 0 1-.2-1.9z"/>
<circle cx="142.1" cy="171.9" r=".63"/>
<circle cx="66" cy="129.5" r=".25"/>
</g>
<path d="M149.1 37.6h1.5v3.5h-1.5zM149.1 66.2h1.5v3.5h-1.5zM231 108.1h1.5v3.5h-1.5zM239.9 108.1h1.5v3.5h-1.5zM50.7 124h1.5v3.5h-1.5zM160.1 121.2h3.6v1.5h-3.6z" fill="none" stroke="#840000" stroke-width=".2"/>
<g fill="none" stroke="#840000" stroke-width="1.3">
<circle cx="56.5" cy="189.2" r="1.27"/>
<circle cx="66" cy="189.2" r="1.27"/>
</g>
<g fill="#ffffc2" stroke="#ffffc2" stroke-width=".18">
<path d="M31.1 113h2.6v5.1h-2.6z"/>
<path d="M189.9 111.8h15.2v17.7h-15.2z"/>
</g>
<path d="M122.6 116.8l10.1 5.1-10.1 5.1z" fill="#ffffc2"/>
<path d="M108.6 102.5h5.1v2h-5.1zM122.6 116.8l10.1 5.1-10.1 5.1z" fill="none" stroke="#840000" stroke-width=".25"/>
<g fill="none" stroke="#840000" stroke-width=".18">
<path d="M149.9 24.1v.8M149.9 28.4v.8M149.9 52.7v.8M149.9 57v.8M258.4 97.8h2.6M261 92.7h13.3v59.7h-13.3zM51.4 115.6v.7M51.4 119.9v.8M80 105.4l-.8 1.3M80 105.4v2.6M80 105.4l.8 1.3M87 116.8v1.3h1.3l-1.3 1.3-1.3-1.3h1.3"/>
<path d="M87 110.5v2M87 113.5v2.1M107.3 103.5h1.3M113.7 103.5h1.2M120 119.4h2.6M258.4 100.3h2.6M258.4 102.9h2.6M258.4 108h2.6M258.4 110.5h2.6M258.4 113h2.6M258.4 115.6h2.6M120 124.5h2.6"/>
<path d="M132.7 121.9h2.6M167.6 133.4v1.2h1.3l-1.3 1.3-1.2-1.3h1.2M216.5 137.8v2.8M230.5 136.5l-.8 1.3M230.5 136.5v2.6M230.5 136.5l.8 1.3M258.4 121.9h2.6M258.4 124.5h2.6M258.4 133.4h2.6M258.4 135.9h2.6M258.4 138.4h2.6M258.4 130.8h2.6"/>
<path d="M197.5 148.6v1.3h1.3l-1.3 1.2-1.3-1.2h1.3M211.5 141.6h3M214.8 140.9l.7-.3v2a1.02 1.02 0 0 1-.9-.6 1.02 1.02 0 0 1 .2-1.1zM217.6 140.6a1.02 1.02 0 0 1 1 1 1.02 1.02 0 0 1-1 1zM218.6 141.6h3M258.4 149.9h2.6M258.4 141h2.6M258.4 143.5h2.6"/>
</g>
<g fill="none" stroke="#006464" stroke-width=".18">
<path d="M274.2 89.9l.3 .1 .1 .2v.4l-.4 .2M275.2 89.5v1.1l.1 .2M275.8 90.3l.6-.1-.1-.2-.3-.1-.2 .2v.6h.5M80.9 102.8h.8l-.5 .5M81.4 103.3l.3 .2v.4l-.3 .2M94.1 114.3h.6M112.8 100.4l.4 .5M113.2 100.1l-.5 .5M123 119.5h1M133.6 114.8l.6 .7M134.2 114.3l-.8 .7M135.3 114.3h-.6v.6l.1-.2 .5 .1 .1 .2-.1 .4-.2 .1-.4-.1"/>
<path d="M231.4 133.9h.8l-.5 .5M231.9 134.4l.3 .3v.3l-.3 .2"/>
</g>
<path d="M149.1 24.9h1.5v3.5h-1.5zM149.1 53.5h1.5v3.5h-1.5zM50.7 116.3h1.5v3.6h-1.5z" fill="none" stroke="#840000" stroke-width=".2"/>
<path d="M85.5 113.5h3" fill="none" stroke="#840000" stroke-width=".33"/>
<path d="M85.5 112.5h3" fill="none" stroke="#840000" stroke-width=".3"/>
<g fill="#840000" stroke="#840000" stroke-width=".18">
<path d="M217.6 140.6a1.02 1.02 0 0 1 1 1 1.02 1.02 0 0 1-1 1z"/>
<path d="M216 140.6h1v2h-1z"/>
<path d="M214.8 140.9l.7-.3v2a1.02 1.02 0 0 1-.9-.6 1.02 1.02 0 0 1 .2-1.1z"/>
</g>
<path d="M261 92.7h13.3v59.7h-13.3z" fill="#ffffc2" stroke="#ffffc2" stroke-width=".18"/>
<path d="M260 135.5h.7" fill="none" stroke="#a90000" stroke-width=".18"/>
<path d="M77.5 119.4l10.1 5.1-10.1 5z" fill="#ffffc2"/>
<g fill="none" stroke="#840000" stroke-width=".25">
<path d="M44.1 38.1v3.8M44.6 37.7v1M44.6 39.5v1M187.2 31.4v1M187.2 33.1v1.1M187.2 34.9v1M187.7 31.8v3.8M224.2 26h17.7v25.4h-17.7zM33.7 48.3h2.5v15.2h-2.5zM44.6 41.3v1M184.4 51.3h2l-1 1.5zM184.4 52.8h2"/>
<path d="M211.5 89.5h2.5v10.2h-2.5zM77.5 119.4l10.1 5.1-10.1 5z"/>
<circle cx="186.3" cy="33.7" r="2.79"/>
<circle cx="45.5" cy="40" r="2.79"/>
</g>
<g fill="none" stroke="#840000" stroke-width=".18">
<path d="M114.9 15.2l-.7 1.3M114.9 15.2v2.6M114.9 15.2l.8 1.3M44.6 38.2h2.5v3.6h-2.5M46.4 26v.8M46.4 30.4v.7M46.4 34.9v3.3M46.6 39.5l.1 .1h.8l.1 .2M47.1 39.6l.4 .7h-.8zM56.5 34.9h2.6M60.1 33.7a2.54 2.54 0 0 1 3 0M64.1 34.9h2.6"/>
<path d="M74.9 34.9h2.6M77.5 30.5h25.4v29.8h-25.4zM90.8 27.9v2.6M102.9 34.9h2.5M114.9 24.8v2M114.9 27.8v2M160.7 34.3v2M160.7 37.3v2.1M184.7 33.3l.3 .6h-.7zM185.2 33.1l-.2 .2h-.7l-.2 .1M185.4 28.6v5.1h1.8M185.4 35.4v3.3"/>
<path d="M187.2 31.9h-2.5v3.5h2.5M187.7 33.7h5.3M197.5 28.6v.7M197.5 32.9v.8M205.1 38.7v2.1M221.6 33.7h2.6M221.6 38.7h2.6M221.6 28.6h2.6M221.6 36.2h2.6M241.9 33.7h2.6M241.9 38.7h2.6M241.9 28.6h2.6"/>
<path d="M250.8 28.6v.7M250.8 32.9v.8M250.8 38.7v.8M257.2 33.7h.7M257.2 38.7h.7M261.5 33.7h.8M261.5 38.7h.8M267.3 33.7v2M267.3 36.7v2M273.7 24.8l-.8 1.2M273.7 24.8v2.5M273.7 24.8l.7 1.2"/>
<path d="M26.7 41.9l-.8 1.3M26.7 41.9v2.6M26.7 41.9l.7 1.3M29.8 49.5h3.9M29.8 52.1h3.9M29.8 54.6h3.9M29.8 57.2h3.9M29.8 59.7h3.9M33.7 59.6h1.2v.2h-1.2zM33.7 57h1.2v.3h-1.2zM33.7 54.5h1.2v.2h-1.2zM33.7 51.9h1.2v.3h-1.2z"/>
<path d="M33.7 49.4h1.2v.3h-1.2zM38.7 40h5.4M44.6 40h1.8v5.1M46.4 47v1.3h1.2l-1.2 1.2-1.3-1.2h1.3M74.9 48.9h2.6M74.9 45.1h2.6M102.9 54h2.5M102.9 50.2h2.5M102.9 40.6h2.5M102.9 44.5h2.5M139.1 57.8h2.5M184.1 51.6l-.5 .5v-.3v.3h.3"/>
<path d="M184.7 52.1l-.6 .5v-.3v.3h.3M185.4 42.5v.8M185.4 49.5v5.1M205.1 41.8v2M216.5 43.8v2M216.5 46.9v2M221.6 48.9h2.6M221.6 43.8h2.6M231.8 51.4v2.6M234.3 51.4v2.6M241.9 48.9h2.6M241.9 43.8h2.6"/>
<path d="M249.6 50.8v2M249.6 53.8v2.1M250.8 43.1v.7M255.9 50.8v2M255.9 53.8v2.1M29.8 62.2h3.9M33.7 62.1h1.2v.3h-1.2zM88.9 60.3v2.6M90.8 67.9v1.3h1.3l-1.3 1.3-1.3-1.3h1.3M92.7 60.3v2.6M126.4 60.3h2.5M139.1 62.9h2.5"/>
<path d="M160.7 68.6v1.3h1.2l-1.2 1.2-1.3-1.2h1.3M160.7 62.9v2M160.7 65.9v2M212.7 90.7h1.3v.2h-1.3zM212.7 93.2h1.3v.3h-1.3zM212.7 95.8h1.3v.2h-1.3zM212.7 98.3h1.3v.3h-1.3zM214 98.4h3.8M214 95.9h3.8M214 93.3h3.8M214 90.8h3.8M226.7 82.6l-.8 1.2"/>
<path d="M226.7 82.6v2.5M226.7 82.6l.8 1.2M246.4 89.9a2.54 2.54 0 0 0 0 3.1M247.6 82.6v2.5M247.6 86.4v2.5M247.6 94v2.5M247.6 82.6l-.7 1.2M247.6 82.6l.8 1.2M258.4 97.8h2.6M80 116.8v3.9M258.4 100.3h2.6M258.4 102.9h2.6"/>
<path d="M258.4 108h2.6M258.4 110.5h2.6M258.4 113h2.6M258.4 115.6h2.6M51.4 123.2v.8M51.4 127.5v.8M66 121.9v3.8M66 133.4v3.8M68.6 129.5h2.5M74.9 121.9h2.6M74.9 127h2.6M80 128.3v3.8"/>
<path d="M87.6 124.5h2.6M258.4 124.5h2.6M258.4 121.9h2.6M258.4 133.4h2.6M258.4 135.9h2.6M258.4 138.4h2.6M258.4 130.8h2.6M101.6 157.5v3.8M108.6 158.8v2.7M120 159.4h2.6M252.7 150.5v1.3h1.3l-1.3 1.2-1.2-1.2h1.2M258.4 149.9h2.6"/>
<path d="M258.4 141h2.6M258.4 143.5h2.6M101.6 168.9v3.8M108.6 163.6v2.8M120 164.5h2.6M132.7 161.9h2.6M134.6 189.9h.1M146.7 189.9h.1"/>
<circle cx="59.6" cy="34.9" r=".51"/>
<circle cx="63.6" cy="34.9" r=".51"/>
<circle cx="247.7" cy="89.4" r=".51"/>
<circle cx="247.7" cy="93.5" r=".51"/>
</g>
<g fill="none" stroke="#006464" stroke-width=".18">
<path d="M120.3 15.2h.7l-.4 .5M120.8 15.7l.2 .2v.3l-.2 .3M28.5 40l-.4 1.2M86.1 35.5h.6M86.1 34.2h.6M109.2 27.3v1.2M167.7 37.4h.6M181.3 34.2h.6M181.4 34.7h.3l.2 .3-.1 .5h-.4M228 36.3h.9M238.8 24.1h.5l.2 .2-.1 .4h-.6M239.1 24.7l.4 .7"/>
<path d="M239.6 38.8h1M256.4 31.7h.9l-.6 1.3M274.6 22.2h.7l-.4 .5M275.1 37.4h.6M275.1 22.7l.2 .2v.3l-.2 .2M46.6 57.5h.5M47 58.4h.1M47.5 57.9l.6-.1-.1-.2-.3-.1-.2 .2v.6h.5M55.2 57.5l.2 .2v.7M56.2 41.4h.7M56.8 41v.9M62.2 57.6l.1 .2-.1 .5"/>
<path d="M202.1 41.9h.6M226.7 49h1M239.6 43.9h1M246.4 53.7h.6M256.6 42.4l.1 .2-.1 .5M263 53.7h.6M276.5 53.3h.8l-.5 .5 .4 .1v.5l-.2 .2-.5-.1M142.8 66.7l.6-.1 .1-.2-.1-.3-.6-.1v1.3M143.1 66.7l.4 .6M167.7 66h.6M248.5 80h.8l-.4 .4M206.4 96.3a1.46 1.46 0 0 1 0 1.9"/>
<path d="M207.8 96.3a1.46 1.46 0 0 0 0 1.9M209 96.5v1.2l-.8-1.2v1.2M209.4 96.3a1.46 1.46 0 0 1 0 1.9M228.5 80.6l-.4 1.3M249.1 80.4l.2 .3v.3l-.2 .2M274.2 89.9l.3 .1 .1 .2v.4l-.4 .2M275.2 89.5v1.1l.1 .2M275.8 90.3l.6-.1-.1-.2-.3-.1-.2 .2v.6h.5M61.1 132.2h.9M62.6 132h.5M63.2 131.4h-.6v1.3M77.9 127.1h1"/>
<path d="M80.1 125.8v1M123 159.5h1M134.9 154.8l.5 .7M135.4 154.3l-.7 .7M136.6 154.3h-.6l-.1 .6 .2-.2 .4 .1 .1 .2v.4l-.2 .1-.5-.1M101.7 166.4v1M119.5 178.3l.5 .7M120 177.8l-.7 .7M121.1 177.8h-.6v.6l.2-.2 .4 .1 .1 .2-.1 .4-.1 .1-.5-.1M136.4 185.4l-.4 1.2"/>
</g>
<g fill="#ffffc2" stroke="#ffffc2" stroke-width=".18">
<path d="M211.5 89.5h2.5v10.2h-2.5z"/>
<path d="M77.5 30.5h25.4v29.8h-25.4z"/>
<path d="M33.7 48.3h2.5v15.2h-2.5z"/>
<path d="M224.2 26h17.7v25.4h-17.7z"/>
</g>
<path d="M243.4 28.2h.8M88.5 60.6v.8M260 135.5h.7" fill="none" stroke="#a90000" stroke-width=".18"/>
<path d="M159.1 37.3h3.1M265.8 36.7h3.1M203.6 41.8h3M215 46.9h3.1M248 53.8h3.1M254.4 53.8h3M159.1 65.9h3.1" fill="none" stroke="#840000" stroke-width=".33"/>
<path d="M159.1 36.3h3.1M265.8 35.7h3.1M203.6 40.8h3M215 45.8h3.1M248 52.8h3.1M254.4 52.8h3M159.1 64.9h3.1" fill="none" stroke="#840000" stroke-width=".3"/>
<g fill="#840000" stroke="#840000" stroke-width=".18">
<path d="M44.8 40l1-.4v.8z"/>
<path d="M275 49.5v1.3h.7l-.7 1.3-.8-1.3h.8z"/>
<path d="M185.7 33.7l1-.4v.7z"/>
<circle cx="46.4" cy="41.8" r=".25"/>
<circle cx="46.4" cy="38.2" r=".25"/>
<circle cx="185.4" cy="31.9" r=".25"/>
<circle cx="185.4" cy="35.4" r=".25"/>
</g>
<path d="M45.6 26.8h1.5v3.6h-1.5zM196.7 29.3h1.5v3.6h-1.5zM250.1 39.5h1.5v3.6h-1.5zM250.1 29.3h1.5v3.6h-1.5zM257.9 32.9h3.6v1.5h-3.6zM257.9 38h3.6v1.5h-3.6zM184.7 43.3h1.5v3.6h-1.5z" fill="none" stroke="#840000" stroke-width=".2"/>
<g fill="none" stroke="#0f0f0f" stroke-width=".18">
<path d="M55.7 33.5h.4l.2 .2-.1 .3h-.5M74.1 34.4h.6M74.1 33.2h.6M247.4 37.7h1M28.6 58.7h.9M28.6 51.1h.9M112.9 43.5h1M113 53h.9M220.3 47.9h1M116.2 113.3h1M114.9 130.9h.8M115.2 129.9l.1-.2v1.2"/>
<path d="M116.2 130.5h1"/>
</g>
<g fill="none" stroke="#0000c2" stroke-width=".25">
<path d="M28.9 89l.4 .1v.2l-.6 .1M29.3 89.8l-.4 .1M38.2 90.6a.72 .72 0 0 0 .1 1.3 .79 .79 0 0 0 0-1.3M39.2 91.9l-.1 .2M75.6 89.7h.3l.1 .3-.6 .1M75.9 90.4l-.3 .1M87.2 89.7h.5M88.7 91.3l-.4 .5 .3 .1v.5l-.2 .2-.4-.1M89.3 92.5l-.1 .2M145.7 89.1h.4l.1 .8M149.6 91.9l-.1 .2M154.8 89l-.3 .1"/>
<path d="M191.2 90.6l-.3 .9h.7M192.5 88.6v.1M192.5 89v.9M192.9 89h.5M193.1 88.6v1.1l.3 .2M197.2 90.6l.4 1.3 .4-1.3"/>
</g>
<g fill="none" stroke="#0000c2" stroke-width=".18">
<path d="M15.9 14.6h153.6v60.3h-153.6zM172.1 14.6h109.8v60.3h-109.8zM59.6 24.2l.2 .3-.6 .2M59.7 25l-.1 .1M63.5 26.3l-.3 .1M70.5 24.2l.2 .3-.6 .2M70.7 25l-.2 .1M157.5 77.5v103.5h-141.6v-103.5h266v79.3h-124.4M188.7 61.3h1M191.1 65.1h.5M191.1 73.3h.5M191.3 64.6v1.1l.3 .2"/>
<path d="M191.3 72.9v1.1l.3 .1M192.8 63l.3 .1M192.8 71.2l.3 .1M193.1 63v1l-.1 .2M193.1 71.2v1.1l-.1 .1M193.1 63.8l-.3 .1M193.1 72l-.3 .1M198.3 60.6l.5-.1 .3 .4-.8 .9h.8M203.3 65.1h.1M203.3 73.3h.1M203.8 65.8v.1M203.8 65.1v.1"/>
<path d="M203.8 73.4v.1M203.8 74v.1M210.2 63.4h1M210.2 71.6h1M211.4 61.2h.5M211.8 63l1 .4-1 .3M211.8 71.2l1 .4-1 .4M211.9 60.5h-.5v1.3M215.7 69.4h1M215.7 69.7h1M217.8 63.2h1M217.8 63.6h1"/>
<path d="M217.8 71.4h1M217.8 71.8h1M218.2 68.8h.8M218.2 69.9l.5 .1M219.5 61.1h1M219.5 61.5h1M220.5 70.8l-.2 .3 .2 .3-.2 .1v.3l.2 .3M220.5 62.6l-.2 .2 .2 .3-.2 .1v.4l.2 .3M222 61.3h1M222.1 68.8l.4 1.2 .4-1.2M227.4 60.5l.4 1.3 .5-1.3M227.8 62.6a.43 .43 0 0 0-.5 .4v.4a.43 .43 0 0 0 .5 .5"/>
<path d="M227.8 70.8a.43 .43 0 0 0-.5 .4v.5a.43 .43 0 0 0 .5 .4M244.6 67h1M251.9 62.6v.8M254.9 66.8l-.2 .2-.4-.1-.1-.1 .1-.5 .4-.1 .2 .1a.84 .84 0 0 1-.3 1.2h-.3M261 62.9l.2 .2-.2 .3M261 62.5l.1 .1M261.7 63.2v.2M261.7 62.6v.1M48.3 85.7v92.1M96.5 81.3v96.5M99.1 82.6h35.5v13.9h-35.5zM106.9 84h.4"/>
<path d="M107 92.3v.8M107.3 84v1l-.3 .3M107.3 84.8h-.4M107.6 91.8v1.1l.3 .2M108.1 88.1h.5M108.5 88.9h.1M108.7 94.3h-.3l-.2 .2v.1l.5 .2v.3h-.5M109.3 95v.1M116.2 88.1l.1 .3-.6 .1M116.3 88.9h-.1M118.5 92.2h.4M118.6 91.8v1.1l.3 .2"/>
<path d="M118.9 84l.2 .3-.6 .1M119.1 84.8h-.2M119.8 92.3l-.3-.1-.2 .2 .1 .2 .4 .1v.3h-.5M121.8 89.7v1.1l.3 .2M125 88.8v.1M132.3 91.8v1.1l.3 .2M256.4 82l.2 .3-.6 .2M256.4 83.7v1.1l.2 .1M256.6 82.8l-.2 .1M125.7 127.6h28.6v6.4h-28.6zM133.7 128.4v.1M133.7 128.8v.7"/>
<path d="M134.1 128.8v.7M134.1 128.9l.4-.1 .1 .7M142.6 128.8h.3l.1 .7M144.1 131.8l.1-.1a.54 .54 0 0 1 .4 .5 .54 .54 0 0 1-.4 .6l-.1-.1M145 131.7v1.1M145.1 132.4l.3 .4M145.4 132.1l-.4 .4M145.7 131.6a1.16 1.16 0 0 1 0 1.5M147.2 132.3v.1M151.5 132.7l.3 .1M151.5 132.1v1M151.8 132.1h-.3"/>
<path d="M210.8 132.8v.1M210.8 132.1v.1M224.4 129l.1 .1M224.5 129l-.1 1.2M224.5 129.8l-.1 .1M231.7 129h.2M232.2 127.7h.5M232.2 127h.4l.2 .3-.6 .1M240.3 127.4h.3l.1 .2-.2 .2h-.2M240.3 127h.3M70.2 146.5v.8M70.2 146.6l.2-.1 .3 .1 .1 .7"/>
<path d="M71.4 146.6h.4l.1 .7M71.9 146.8l-.4 .1-.2 .1 .2 .3h.4M72.5 146.1v1.1l.2 .1M159.4 142.2h32.4v11.5h-32.4zM160.6 152.3h1M162.2 151.9l1 .4-1 .3M164.2 149.8h.5M164.7 149.4l-.3 .1M168.7 146.5h.5M168.7 145.8l.4-.1 .2 .3-.6 .2M169.8 146.2l.6-.2-.1-.2-.3-.1-.2 .2v.6h.5M171.9 147.9h.3"/>
<path d="M172.2 147.9l.2 .3v.2l-.1 .2h-.4M172.4 147.5v.2l-.2 .2M179.8 149.8h.4M179.9 149.6v1.1M181.2 149.9l-.4-.1-.2 .3 .1 .5h.5M181.8 149.5a1.47 1.47 0 0 1-.2 1.7M188.1 145.9l.2-.2 .3 .1v.8M188.1 145.7v.9M15.9 184.2h81.3v10.1h-81.3zM101 184.2h56.5v10.1h-56.5z"/>
</g>
<path d="M225.7 151.5h.5M225.7 150.2h.5M225.7 150.8h.5" fill="none" stroke="#f00" stroke-width=".25"/>
<path d="M218.9 17.7l-.8 .1-.2 .4v.7l.1 .2 .4 .3h.5M232.8 17.8l.7-.1 .5 .5v.7l-.3 .4-.2 .1-.7-.1M232.8 17.7v2.5M245 18.4h1.9M253.1 17l-1-.2v2.6l1-.1M56.5 80.5v1.7M57.2 80.5a.65 .65 0 0 0-.7 .5M200.1 80.5h.9M200.8 82.2h.2" fill="none" stroke="#0000c2" stroke-width=".51"/>
<g fill="none" stroke="#009600" stroke-width=".18">
<path d="M73.7 17.8v1.3M90.8 17.8v10.1M107.3 17.8v17.1h-1.9M46.4 31.1v3.8h10.1M66.7 34.9h8.2M73.7 24.1v1.3M114.9 24.8v-7h-68.5v8.2M114.9 29.8v2M126.4 31.8h-3.8v6.3M141.6 34.3h3.8v10.2M145.4 21.6v7.6h-3.8M149.9 24.1v-2.5h-31.8v19h-12.7"/>
<path d="M149.9 29.2v7.6M149.9 33h10.8v1.3M160.7 39.4v.6M177.2 27.9v.7h44.4M185.4 38.7v3.8M193 33.7h28.6M205.1 28.6v10.1M212.1 28.6v8.9h7.6M221.6 36.2h-1.9v2.5h1.9M244.5 38.7h12.7M244.5 33.7h12.7M262.3 38.7h1.9"/>
<path d="M262.3 33.7h1.9v25.4M267.3 28.6v5.1M267.3 38.7v22.9M273.7 27.3v1.3h-29.2M26.7 44.5v5h3.1M37.5 40h1.2M46.4 45.1v1.9M60.3 48.9h14.6M60.3 45.1h14.6M105.4 50.2h44.5v2.5M105.4 54h12.7v19h31.8v-2.5M145.4 50.2v7.6h-3.8"/>
<path d="M149.9 41.9v2.6h-44.5M149.9 57.8v7.6M185.4 54.6v4.5h81.9M185.4 47.6v1.9M205.1 43.8v15.3M216.5 43.8h5.1M216.5 48.9h5.1M231.8 54v5.1M234.3 54v1.9h-2.5M244.5 43.8h30.5v5.7M244.5 48.9h5.1v1.9M249.6 55.9v3.2"/>
<path d="M255.9 43.8v7M255.9 55.9v3.2M29.8 62.2h-3.1v5.1M88.9 62.9v1.9h3.8v-1.9M90.8 64.8v3.1M126.4 60.3h-3.8v6.4M141.6 62.9h3.8v10.1M149.9 61.6h10.8v1.3M160.7 67.9v.7M167.6 99.7h29.9v9.5M167.6 92.1v9.5M217.8 93.3h8.9v31.2"/>
<path d="M217.8 98.4h2.5v5.1M217.8 95.9h5.7v26M226.7 85.1v5.7h-8.9M231.8 91.4v15.9M231.8 97.2h8.9v10.1M242.6 92.1v8.2h15.8M247.6 96.5v1.3h10.8M247.6 85.1v1.3M37.5 114.3h13.9v1.3M37.5 116.8h1.2v22.9M80 108v8.8M80 108.6h7v1.9"/>
<path d="M87 115.6v1.2M107.3 103.5h-7.6v21M114.9 103.5h5.1M117.5 103.5v15.9h2.5M127.6 103.5h12.1v18.4M167.6 109.2v1.3M187.3 119.4h-10.1v20.3h-45.1M231.8 112.4v9.5M240.7 112.4v12.1M256.5 100.3v2.6h1.9M51.4 121.9h23.5M51.4 120.7v2.5"/>
<path d="M51.4 128.3v10.1M66 137.2v.6M80 132.1v17.1M90.2 124.5h17.1M94.6 124.5v11.4h-21.6v-8.9h1.9M114.9 124.5h5.1M117.5 139.7h7M117.5 124.5v34.9h2.5M135.3 121.9h24.1M139.7 139.7v22.2h-4.4M164.5 121.9h22.8M167.6 121.9v3.8"/>
<path d="M167.6 130.8v2.6M197.5 132.1v16.5M207.6 121.9h50.8M207.6 124.5h50.8M207.6 127h8.9v10.8M230.5 139.1v2.5h-8.9M256.5 130.8h1.9M80 141h7.6M87.6 146.1v3.1M101.6 156.2h7v2.6M101.6 154.9v2.6M117.5 149.2h7"/>
<path d="M132.1 149.2h7.6M197.5 141.6h14M258.4 149.9h-5.7v.6M101.6 172.7v1.9M108.6 166.4v7M120 164.5h-2.5v8.9h-15.9"/>
</g>
<g fill="none" stroke="#000084" stroke-width=".18">
<path d="M207 116.2l1.3 1.2M208.3 116.2l-1.3 1.2M257.8 115l1.3 1.2M257.8 107.3l1.3 1.3M257.8 109.9l1.3 1.2M257.8 112.4l1.3 1.2M259.1 115l-1.3 1.2M259.1 107.3l-1.3 1.3M259.1 109.9l-1.3 1.2M259.1 112.4l-1.3 1.2M70.5 128.9l1.2 1.2M71.7 128.9l-1.2 1.2"/>
<path d="M186.7 126.4l1.2 1.2M186.7 123.9l1.2 1.2M187.9 126.4l-1.2 1.2M187.9 123.9l-1.2 1.2M257.8 132.7l1.3 1.3M257.8 135.3l1.3 1.2M257.8 137.8l1.3 1.2M259.1 132.7l-1.3 1.3M259.1 135.3l-1.3 1.2M259.1 137.8l-1.3 1.2M257.8 140.4l1.3 1.2M257.8 142.9l1.3 1.2"/>
<path d="M259.1 140.4l-1.3 1.2M259.1 142.9l-1.3 1.2"/>
</g>
<g fill="#009600" stroke="#009600" stroke-width=".18">
<circle cx="101.6" cy="156.2" r=".46"/>
<circle cx="117.5" cy="149.2" r=".46"/>
<circle cx="139.7" cy="149.2" r=".46"/>
<circle cx="117.5" cy="139.7" r=".46"/>
<circle cx="139.7" cy="139.7" r=".46"/>
<circle cx="139.7" cy="121.9" r=".46"/>
<circle cx="66" cy="121.9" r=".46"/>
<circle cx="80" cy="108.6" r=".46"/>
<circle cx="51.4" cy="121.9" r=".46"/>
<circle cx="80" cy="141" r=".46"/>
<circle cx="101.6" cy="173.4" r=".46"/>
<circle cx="108.6" cy="173.4" r=".46"/>
<circle cx="94.6" cy="124.5" r=".46"/>
<circle cx="99.7" cy="124.5" r=".46"/>
<circle cx="117.5" cy="124.5" r=".46"/>
<circle cx="117.5" cy="103.5" r=".46"/>
<circle cx="212.1" cy="28.6" r=".46"/>
<circle cx="197.5" cy="28.6" r=".46"/>
<circle cx="205.1" cy="28.6" r=".46"/>
<circle cx="185.4" cy="28.6" r=".46"/>
<circle cx="205.1" cy="59.1" r=".46"/>
<circle cx="219.7" cy="37.5" r=".46"/>
<circle cx="197.5" cy="33.7" r=".46"/>
<circle cx="231.8" cy="55.9" r=".46"/>
<circle cx="231.8" cy="59.1" r=".46"/>
<circle cx="247.6" cy="97.8" r=".46"/>
<circle cx="256.5" cy="100.3" r=".46"/>
<circle cx="149.9" cy="61.6" r=".46"/>
<circle cx="197.5" cy="141.6" r=".46"/>
<circle cx="167.6" cy="99.7" r=".46"/>
<circle cx="167.6" cy="121.9" r=".46"/>
<circle cx="145.4" cy="44.5" r=".46"/>
<circle cx="145.4" cy="50.2" r=".46"/>
<circle cx="250.8" cy="33.7" r=".46"/>
<circle cx="250.8" cy="28.6" r=".46"/>
<circle cx="255.9" cy="59.1" r=".46"/>
<circle cx="264.2" cy="59.1" r=".46"/>
<circle cx="250.8" cy="43.8" r=".46"/>
<circle cx="250.8" cy="38.7" r=".46"/>
<circle cx="267.3" cy="59.1" r=".46"/>
<circle cx="255.9" cy="43.8" r=".46"/>
<circle cx="249.6" cy="59.1" r=".46"/>
<circle cx="267.3" cy="28.6" r=".46"/>
<circle cx="264.2" cy="38.7" r=".46"/>
<circle cx="231.8" cy="121.9" r=".46"/>
<circle cx="240.7" cy="124.5" r=".46"/>
<circle cx="226.7" cy="124.5" r=".46"/>
<circle cx="231.8" cy="97.2" r=".46"/>
<circle cx="223.5" cy="121.9" r=".46"/>
<circle cx="145.4" cy="21.6" r=".46"/>
<circle cx="145.4" cy="73" r=".46"/>
<circle cx="73.7" cy="17.8" r=".46"/>
<circle cx="90.8" cy="17.8" r=".46"/>
<circle cx="107.3" cy="17.8" r=".46"/>
<circle cx="114.9" cy="17.8" r=".46"/>
<circle cx="90.8" cy="64.8" r=".46"/>
<circle cx="149.9" cy="33" r=".46"/>
<circle cx="46.4" cy="34.9" r=".46"/>
</g>
<use href="#words"/>
</svg>
